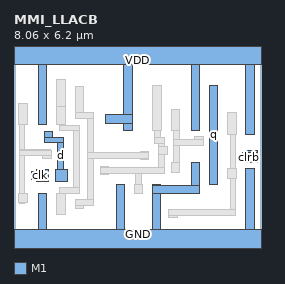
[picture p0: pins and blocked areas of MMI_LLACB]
MACRO MMI_LLACB
	CLASS CORE ;
	FOREIGN MMI_LLACB 0 0 ;
	SIZE 8.06 BY 6.2 ;
	SYMMETRY X Y ;
	SITE CORE1 ;
	PIN d
		DIRECTION input ;
		USE SIGNAL ;
		PORT
			LAYER M1 ;
			RECT 0.99 3.425 1.27 3.59 ;
			LAYER M1 ;
			RECT 0.99 3.235 1.62 3.425 ;
			LAYER M1 ;
			RECT 1.425 2.38 1.62 3.235 ;
			LAYER M1 ;
			RECT 1.34 2.355 1.62 2.38 ;
			LAYER M1 ;
			RECT 1.34 1.98 1.74 2.355 ;
		END
		AntennaGateArea 0.3465 ;
	END d
	PIN GND
		DIRECTION inout ;
		USE GROUND ;
		PORT
			LAYER M1 ;
			RECT 0.795 0.42 1.075 1.59 ;
			LAYER M1 ;
			RECT 3.33 0.42 3.61 1.885 ;
			LAYER M1 ;
			RECT 4.51 1.85 4.79 1.885 ;
			LAYER M1 ;
			RECT 5.785 1.85 6.065 2.58 ;
			LAYER M1 ;
			RECT 4.51 1.57 6.065 1.85 ;
			LAYER M1 ;
			RECT 4.51 0.42 4.79 1.57 ;
			LAYER M1 ;
			RECT 7.555 0.42 7.835 2.385 ;
			LAYER M1 ;
			RECT 0 -0.42 8.06 0.42 ;
		END
	END GND
	PIN q
		DIRECTION output ;
		USE SIGNAL ;
		PORT
			LAYER M1 ;
			RECT 6.375 1.88 6.655 5.105 ;
		END
		AntennaDiffArea 0.91245 ;
	END q
	PIN VDD
		DIRECTION inout ;
		USE POWER ;
		PORT
			LAYER M1 ;
			RECT 0 5.78 8.06 6.62 ;
			LAYER M1 ;
			RECT 0.795 3.835 1.075 5.78 ;
			LAYER M1 ;
			RECT 3.575 4.145 3.855 5.78 ;
			LAYER M1 ;
			RECT 2.99 3.86 3.855 4.145 ;
			LAYER M1 ;
			RECT 3.575 3.635 3.855 3.86 ;
			LAYER M1 ;
			RECT 5.785 3.635 6.065 5.78 ;
			LAYER M1 ;
			RECT 7.555 3.52 7.835 5.78 ;
		END
	END VDD
	PIN clk
		DIRECTION input ;
		USE CLOCK ;
		PORT
			LAYER M1 ;
			RECT 0.735 2.305 1.12 2.355 ;
			LAYER M1 ;
			RECT 0.575 2.025 1.12 2.305 ;
			LAYER M1 ;
			RECT 0.735 1.98 1.12 2.025 ;
		END
		AntennaGateArea 0.34125 ;
	END clk
	PIN clrb
		DIRECTION input ;
		USE SIGNAL ;
		PORT
			LAYER M1 ;
			RECT 7.56 2.905 7.94 2.98 ;
			LAYER M1 ;
			RECT 7.445 2.625 7.94 2.905 ;
			LAYER M1 ;
			RECT 7.56 2.6 7.94 2.625 ;
		END
		AntennaGateArea 0.17325 ;
	END clrb
	OBS
		LAYER M1 ;
		RECT 0.16 3.835 0.44 4.535 ;
		LAYER M1 ;
		RECT 1.385 4.435 1.665 5.305 ;
		LAYER M1 ;
		RECT 1.385 3.835 1.67 4.435 ;
		LAYER M1 ;
		RECT 1.995 4.21 2.275 5.075 ;
		LAYER M1 ;
		RECT 1.995 4.015 2.6 4.21 ;
		LAYER M1 ;
		RECT 0.165 3.015 0.355 3.835 ;
		LAYER M1 ;
		RECT 1.475 3.815 1.67 3.835 ;
		LAYER M1 ;
		RECT 1.475 3.625 2.145 3.815 ;
		LAYER M1 ;
		RECT 0.165 2.99 1.195 3.015 ;
		LAYER M1 ;
		RECT 0.165 2.825 1.21 2.99 ;
		LAYER M1 ;
		RECT 0.165 1.59 0.355 2.825 ;
		LAYER M1 ;
		RECT 0.93 2.71 1.21 2.825 ;
		LAYER M1 ;
		RECT 1.95 1.77 2.145 3.625 ;
		LAYER M1 ;
		RECT 1.475 1.59 2.145 1.77 ;
		LAYER M1 ;
		RECT 0.16 1.275 0.44 1.59 ;
		LAYER M1 ;
		RECT 0.165 1.255 0.355 1.275 ;
		LAYER M1 ;
		RECT 1.385 1.575 2.145 1.59 ;
		LAYER M1 ;
		RECT 2.405 2.91 2.6 4.015 ;
		LAYER M1 ;
		RECT 4.535 3.635 4.815 5.105 ;
		LAYER M1 ;
		RECT 5.125 3.635 5.405 4.335 ;
		LAYER M1 ;
		RECT 4.57 3.415 4.765 3.635 ;
		LAYER M1 ;
		RECT 4.57 3.22 4.925 3.415 ;
		LAYER M1 ;
		RECT 4.73 3.13 4.925 3.22 ;
		LAYER M1 ;
		RECT 5.215 3.345 5.405 3.635 ;
		LAYER M1 ;
		RECT 5.895 3.345 6.175 3.435 ;
		LAYER M1 ;
		RECT 5.215 3.155 6.175 3.345 ;
		LAYER M1 ;
		RECT 5.215 3.15 6.05 3.155 ;
		LAYER M1 ;
		RECT 4.115 2.91 4.395 2.96 ;
		LAYER M1 ;
		RECT 2.405 2.715 4.395 2.91 ;
		LAYER M1 ;
		RECT 1.385 0.89 1.665 1.575 ;
		LAYER M1 ;
		RECT 2.405 1.375 2.6 2.715 ;
		LAYER M1 ;
		RECT 4.115 2.68 4.395 2.715 ;
		LAYER M1 ;
		RECT 4.73 2.85 5.015 3.13 ;
		LAYER M1 ;
		RECT 2.81 2.42 3.09 2.47 ;
		LAYER M1 ;
		RECT 4.73 2.42 4.925 2.85 ;
		LAYER M1 ;
		RECT 5.215 2.585 5.405 3.15 ;
		LAYER M1 ;
		RECT 2.81 2.23 4.925 2.42 ;
		LAYER M1 ;
		RECT 5.125 2.27 5.405 2.585 ;
		LAYER M1 ;
		RECT 2.81 2.19 3.09 2.23 ;
		LAYER M1 ;
		RECT 3.975 1.885 4.17 2.23 ;
		LAYER M1 ;
		RECT 1.995 1.18 2.6 1.375 ;
		LAYER M1 ;
		RECT 1.995 1.095 2.275 1.18 ;
		LAYER M1 ;
		RECT 3.92 1.57 4.2 1.885 ;
		LAYER M1 ;
		RECT 6.965 3.52 7.245 4.22 ;
		LAYER M1 ;
		RECT 7.05 2.385 7.24 3.52 ;
		LAYER M1 ;
		RECT 6.965 2.07 7.245 2.385 ;
		LAYER M1 ;
		RECT 7.05 1.065 7.24 2.07 ;
		LAYER M1 ;
		RECT 5.04 0.875 7.24 1.065 ;
		LAYER M1 ;
		RECT 5.04 0.785 5.32 0.875 ;
	END
END MMI_LLACB
